VERSION 5.8 ;
BUSBITCHARS "[]" ;
DIVIDERCHAR "/" ;

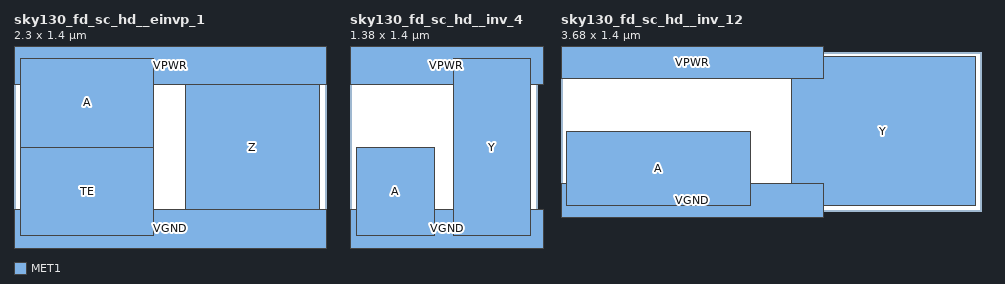
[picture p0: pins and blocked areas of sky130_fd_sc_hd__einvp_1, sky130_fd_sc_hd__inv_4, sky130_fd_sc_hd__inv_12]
MACRO sky130_fd_sc_hd__einvp_1
  CLASS CORE ;
  FOREIGN sky130_fd_sc_hd__einvp_1 ;
  ORIGIN 0 0 ;
  SIZE 2.3 BY 1.4 ;
  SYMMETRY X Y R90 ;
  SITE core7 ;
  PIN A
    DIRECTION INPUT ;  USE SIGNAL ;
    PORT  LAYER MET1 ;  RECT 0.05 0.70 1.03 1.35 ;  END
  END A
  PIN TE
    DIRECTION INPUT ;  USE SIGNAL ;
    PORT  LAYER MET1 ;  RECT 0.05 0.05 1.03 0.70 ;  END
  END TE
  PIN Z
    DIRECTION OUTPUT ;  USE SIGNAL ;
    PORT  LAYER MET1 ;  RECT 1.26 0.05 2.25 1.35 ;  END
  END Z
  PIN VPWR
    DIRECTION INOUT ;  USE POWER ;  SHAPE ABUTMENT ;
    PORT  LAYER MET1 ;  RECT 0 1.16 2.30 1.64 ;  END
  END VPWR
  PIN VGND
    DIRECTION INOUT ;  USE GROUND ;  SHAPE ABUTMENT ;
    PORT  LAYER MET1 ;  RECT 0 -0.24 2.30 0.24 ;  END
  END VGND
END sky130_fd_sc_hd__einvp_1

MACRO sky130_fd_sc_hd__inv_4
  CLASS CORE ;
  FOREIGN sky130_fd_sc_hd__inv_4 ;
  ORIGIN 0 0 ;
  SIZE 1.38 BY 1.4 ;
  SYMMETRY X Y R90 ;
  SITE core7 ;
  PIN A
    DIRECTION INPUT ;  USE SIGNAL ;
    PORT  LAYER MET1 ;  RECT 0.05 0.05 0.62 0.70 ;  END
  END A
  PIN Y
    DIRECTION OUTPUT ;  USE SIGNAL ;
    PORT  LAYER MET1 ;  RECT 0.76 0.05 1.33 1.35 ;  END
  END Y
  PIN VPWR
    DIRECTION INOUT ;  USE POWER ;  SHAPE ABUTMENT ;
    PORT  LAYER MET1 ;  RECT 0 1.16 2.30 1.64 ;  END
  END VPWR
  PIN VGND
    DIRECTION INOUT ;  USE GROUND ;  SHAPE ABUTMENT ;
    PORT  LAYER MET1 ;  RECT 0 -0.24 2.30 0.24 ;  END
  END VGND
END sky130_fd_sc_hd__inv_4

MACRO sky130_fd_sc_hd__inv_12
  CLASS CORE ;
  FOREIGN sky130_fd_sc_hd__inv_12 ;
  ORIGIN 0 0 ;
  SIZE 3.68 BY 1.4 ;
  SYMMETRY X Y R90 ;
  SITE core7 ;
  PIN A
    DIRECTION INPUT ;  USE SIGNAL ;
    PORT  LAYER MET1 ;  RECT 0.05 0.05 1.66 0.70 ;  END
  END A
  PIN Y
    DIRECTION OUTPUT ;  USE SIGNAL ;
    PORT  LAYER MET1 ;  RECT 2.02 0.05 3.63 1.35 ;  END
  END Y
  PIN VPWR
    DIRECTION INOUT ;  USE POWER ;  SHAPE ABUTMENT ;
    PORT  LAYER MET1 ;  RECT 0 1.16 2.30 1.64 ;  END
  END VPWR
  PIN VGND
    DIRECTION INOUT ;  USE GROUND ;  SHAPE ABUTMENT ;
    PORT  LAYER MET1 ;  RECT 0 -0.24 2.30 0.24 ;  END
  END VGND
END sky130_fd_sc_hd__inv_12

END LIBRARY
